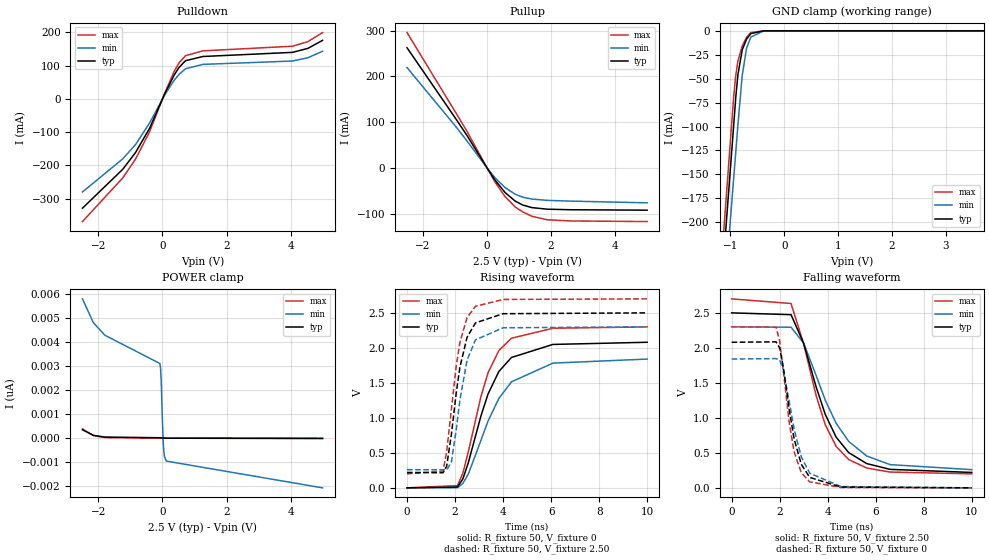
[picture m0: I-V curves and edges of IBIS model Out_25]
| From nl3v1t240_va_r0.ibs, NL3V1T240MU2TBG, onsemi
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|//////////////////////////////////////////////////////////////////////////////
|//////////////////////////////////////////////////////////////////////////////
[Model] Out_25
Model_type 3-state
Polarity Inverting
Enable Active-Low
Vmeas = 1.25
Vref = 2.50
Rref = 2k
Cref = 15pF
|  variable   typ   min   max
C_comp   5.9pF   5.9pF   5.9pF
|//////////////////////////////////////////////////////////////////////////////
[Temperature Range]   25   125   -40
|//////////////////////////////////////////////////////////////////////////////
[Voltage Range]   2.50V   2.30V   2.70V
|//////////////////////////////////////////////////////////////////////////////
[Pulldown Reference]   0V   0V   0V
|//////////////////////////////////////////////////////////////////////////////
[Pullup Reference]   2.50V   2.30V   2.70V
|//////////////////////////////////////////////////////////////////////////////
[GND Clamp Reference]   0V   0V   0V
|//////////////////////////////////////////////////////////////////////////////
[POWER Clamp Reference] 2.50V   2.30V   2.70V
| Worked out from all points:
|   slope of the pulldown table from 0 to 0.375 V, typ, clamps not added: 5.11 ohm
|   slope of the pullup table from 0 to 0.375 V, typ, clamps not added: 9.76 ohm
|   GND clamp passes 1 mA (typ) near -0.56 V on its own axis
|   falling waveform, R_fixture 50, V_fixture 2.50: 20-80 % time 1.43ns typ, 1.65ns min, 1.27ns max; typ from 2.5 V to 0.22 V
|   falling waveform, R_fixture 50, V_fixture 0: 20-80 % time 638ps typ, 708ps min, 545ps max; typ from 2.08 V to 0 V
|   rising waveform, R_fixture 50, V_fixture 0: 20-80 % time 1.23ns typ, 1.48ns min, 1.1ns max; typ from 0 V to 2.08 V
|   rising waveform, R_fixture 50, V_fixture 2.50: 20-80 % time 582ps typ, 568ps min, 563ps max; typ from 0.22 V to 2.5 V
|//////////////////////////////////////////////////////////////////////////////
[Pulldown]
|   Voltage   I(typ)   I(min)   I(max)
-2.5V     -328.6mA   -279.9mA   -368.8mA
-1.24V    -211.6mA   -180.3mA   -237.5mA
-840mV    -161mA     -137.2mA   -180.7mA
-400mV    -87.99mA   -72.01mA   -98.23mA
60mV      12.91mA    10.24mA    14.7mA
360mV     70.87mA    55.51mA    81.68mA
520mV     94.94mA    73.97mA    108.9mA
720mV     114.7mA    90.46mA    129.9mA
1.26V     127.3mA    103.6mA    144.2mA
4.06V     139.7mA    113.7mA    158.2mA
4.54V     151.7mA    123.5mA    171.9mA
5V        175.8mA    143.1mA    199.2mA
|//////////////////////////////////////////////////////////////////////////////
[Pullup]
|   Voltage   I(typ)   I(min)   I(max)
-2.5V     262.5mA    219.2mA    295.7mA
-960mV    105.7mA    88.96mA    118.6mA
-640mV    72.26mA    60.08mA    81.55mA
20mV      -2.298mA   -1.856mA   -2.579mA
240mV     -25.7mA    -20.73mA   -29.81mA
560mV     -53.53mA   -42.75mA   -62.39mA
880mV     -72.54mA   -57.49mA   -85.35mA
1.12V     -81.18mA   -63.97mA   -96.16mA
1.4V      -86.61mA   -67.96mA   -105.6mA
1.88V     -90.09mA   -70.8mA    -113.2mA
2.62V     -91.28mA   -72.48mA   -115.8mA
5V        -92.23mA   -76.17mA   -117.1mA
|//////////////////////////////////////////////////////////////////////////////
[GND Clamp]
|   Voltage   I(typ)   I(min)   I(max)
-2.5V     -1.26A     -1.263A    -1.257A
-1.18V    -278mA     -325.3mA   -252.2mA
-1.1V     -218.4mA   -268.4mA   -191.3mA
-1.04V    -173.8mA   -225.8mA   -145.6mA
-940mV    -99.42mA   -154.7mA   -69.51mA
-900mV    -69.33mA   -126.3mA   -46.26mA
-860mV    -45.54mA   -97.9mA    -31.41mA
-780mV    -19.75mA   -46.28mA   -15.71mA
-700mV    -8.683mA   -18.18mA   -6.734mA
-620mV    -2.857mA   -6.467mA   -1.78mA
-380mV    -1.788uA   -32.75uA   -260.7nA
5V        2.467pA    -432.4pA   -188.9fA
|//////////////////////////////////////////////////////////////////////////////
[POWER Clamp]
|   Voltage   I(typ)   I(min)   I(max)
-2.5V     351.8pA    5.817nA    384.2pA
-2.16V    116.6pA    4.824nA    103.9pA
-1.8V     44.68pA    4.299nA    23pA
-80mV     15.31pA    3.116nA    -251.8fA
-60mV     13.95pA    2.909nA    -252.4fA
-40mV     12.05pA    2.398nA    -252.9fA
0V        7.496pA    617.6pA    -254.1fA
20mV      5.213pA    -116.4pA   -254.6fA
40mV      3.089pA    -528pA     -255.2fA
60mV      1.116pA    -760.2pA   -255.8fA
120mV     -2.571pA   -960.1pA   -257.5fA
5V        -17.02pA   -2.077nA   -395.8fA
|//////////////////////////////////////////////////////////////////////////////
|//////////////////////////////////////////////////////////////////////////////
[Ramp]
|  variable   typ   min   max
dV/dt_r   1.248E+00/1.275E-09  1.104E+00/1.500E-09  1.380E+00/1.125E-09
dV/dt_f   1.368E+00/1.425E-09  1.224E+00/1.650E-09  1.500E+00/1.275E-09
R_load = 50
|/////////////////////////////////////////////////////////////////////////////
[Falling Waveform]
R_fixture = 50
V_fixture = 2.50
V_fixture_min = 2.30
V_fixture_max = 2.70
C_fixture = 0p
|   time   V(typ)   V(min)   V(max)
0s        2.5V       2.3V       2.7V
2.475ns   2.474V     2.295V     2.634V
3ns       2.065V     2.067V     2.057V
3.525ns   1.436V     1.6V       1.311V
3.9ns     1.049V     1.253V     901.9mV
4.35ns    726.2mV    923.9mV    593.2mV
4.875ns   503.5mV    663.4mV    403.9mV
5.625ns   346.7mV    455.2mV    283.2mV
6.6ns     264mV      331.9mV    225.7mV
10ns      220mV      260mV      200mV
|//////////////////////////////////////////////////////////////////////////////
[Falling Waveform]
R_fixture = 50
V_fixture = 0
C_fixture = 0p
|   time   V(typ)   V(min)   V(max)
0s        2.08V      1.84V      2.3V
1.85ns    2.086V     1.847V     2.296V
2ns       1.999V     1.826V     2.098V
2.15ns    1.728V     1.691V     1.682V
2.4ns     1.114V     1.232V     930.7mV
2.6ns     703.1mV    842.4mV    520mV
2.9ns     337.7mV    444.1mV    217.5mV
3.25ns    149.4mV    209.7mV    86.02mV
4.55ns    11.65mV    18.57mV    5.116mV
10ns      0V         0V         0V
|//////////////////////////////////////////////////////////////////////////////
[Rising Waveform]
R_fixture = 50
V_fixture = 0
C_fixture = 0p
|   time   V(typ)   V(min)   V(max)
0s        0V         0V         0V
2.1ns     11.68mV    2.466mV    31.49mV
2.325ns   128.2mV    63.04mV    209.9mV
2.55ns    357.2mV    195.7mV    512.3mV
3.075ns   1.024V     675.9mV    1.302V
3.375ns   1.342V     955.8mV    1.646V
3.825ns   1.663V     1.278V     1.962V
4.35ns    1.863V     1.515V     2.138V
6.075ns   2.049V     1.782V     2.28V
10ns      2.08V      1.84V      2.3V
|//////////////////////////////////////////////////////////////////////////////
[Rising Waveform]
R_fixture = 50
V_fixture = 2.50
V_fixture_min = 2.30
V_fixture_max = 2.70
C_fixture = 0p
|   time   V(typ)   V(min)   V(max)
0s        220mV      260mV      200mV
1.5ns     215.7mV    258.5mV    240.3mV
1.65ns    309.6mV    253.4mV    513.3mV
1.85ns    770mV      373.7mV    1.133V
2.05ns    1.36V      835.7mV    1.745V
2.2ns     1.721V     1.251V     2.075V
2.5ns     2.152V     1.826V     2.434V
2.85ns    2.357V     2.114V     2.594V
4ns       2.488V     2.287V     2.692V
10ns      2.5V       2.3V       2.7V
